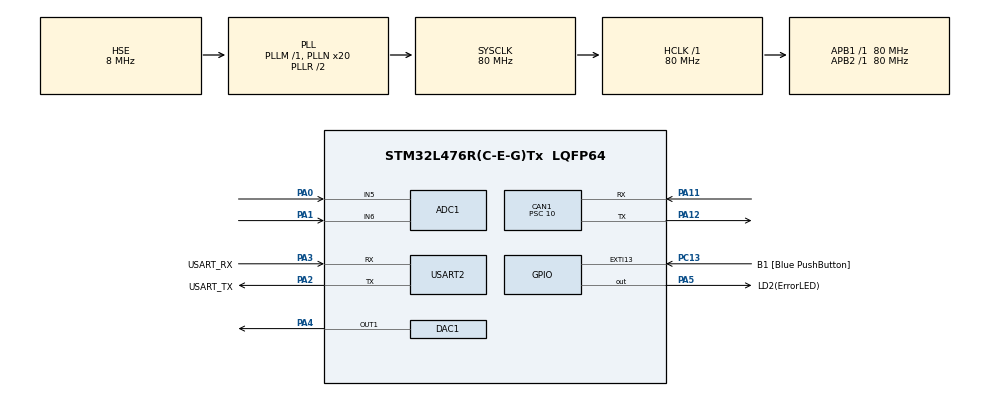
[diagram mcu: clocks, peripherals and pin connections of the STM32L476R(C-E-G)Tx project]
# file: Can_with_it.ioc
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ADC1.Channel-7\#ChannelRegularConversion=ADC_CHANNEL_5
ADC1.Channel-8\#ChannelRegularConversion=ADC_CHANNEL_6
ADC1.ContinuousConvMode=ENABLE
ADC1.DMAContinuousRequests=ENABLE
ADC1.ExternalTrigConv=ADC_EXTERNALTRIG_T6_TRGO
ADC1.ExternalTrigConvEdge=ADC_EXTERNALTRIGCONVEDGE_RISINGFALLING
ADC1.NbrOfConversion=2
ADC1.NbrOfConversionFlag=1
ADC1.OffsetNumber-7\#ChannelRegularConversion=ADC_OFFSET_NONE
ADC1.OffsetNumber-8\#ChannelRegularConversion=ADC_OFFSET_NONE
ADC1.Overrun=ADC_OVR_DATA_PRESERVED
ADC1.Rank-7\#ChannelRegularConversion=1
ADC1.Rank-8\#ChannelRegularConversion=2
ADC1.SamplingTime-7\#ChannelRegularConversion=ADC_SAMPLETIME_247CYCLES_5
ADC1.SamplingTime-8\#ChannelRegularConversion=ADC_SAMPLETIME_247CYCLES_5
ADC1.master=1
CAN1.BS1=CAN_BS1_13TQ
CAN1.BS2=CAN_BS2_2TQ
CAN1.CalculateBaudRate=500000
CAN1.CalculateTimeBit=2000
CAN1.CalculateTimeQuantum=125.0
CAN1.Mode=CAN_MODE_NORMAL
CAN1.Prescaler=10
DAC1.DAC_Trigger-DAC_OUT1=DAC_TRIGGER_T6_TRGO
Dma.ADC1.0.Direction=DMA_PERIPH_TO_MEMORY
Dma.ADC1.0.Instance=DMA1_Channel1
Dma.ADC1.0.MemDataAlignment=DMA_MDATAALIGN_WORD
Dma.ADC1.0.MemInc=DMA_MINC_ENABLE
Dma.ADC1.0.Mode=DMA_CIRCULAR
Dma.ADC1.0.PeriphDataAlignment=DMA_PDATAALIGN_WORD
Dma.ADC1.0.PeriphInc=DMA_PINC_DISABLE
Dma.ADC1.0.Priority=DMA_PRIORITY_VERY_HIGH
Dma.DAC_CH1.1.Direction=DMA_MEMORY_TO_PERIPH
Dma.DAC_CH1.1.Instance=DMA1_Channel3
Dma.DAC_CH1.1.MemDataAlignment=DMA_MDATAALIGN_HALFWORD
Dma.DAC_CH1.1.MemInc=DMA_MINC_ENABLE
Dma.DAC_CH1.1.Mode=DMA_CIRCULAR
Dma.DAC_CH1.1.PeriphDataAlignment=DMA_PDATAALIGN_HALFWORD
Dma.DAC_CH1.1.PeriphInc=DMA_PINC_DISABLE
Dma.DAC_CH1.1.Priority=DMA_PRIORITY_HIGH
Dma.Request0=ADC1
Dma.Request1=DAC_CH1
Mcu.Family=STM32L4
Mcu.Name=STM32L476R(C-E-G)Tx
Mcu.Package=LQFP64
NVIC.CAN1_RX0_IRQn=true\:1\:0\:true\:false\:true\:true\:true\:true
NVIC.CAN1_RX1_IRQn=true\:1\:0\:true\:false\:true\:true\:true\:true
NVIC.CAN1_SCE_IRQn=true\:1\:0\:true\:false\:true\:true\:true\:true
NVIC.CAN1_TX_IRQn=true\:1\:0\:true\:false\:true\:true\:true\:true
NVIC.DMA1_Channel1_IRQn=true\:0\:0\:true\:false\:true\:false\:true\:true
NVIC.DMA1_Channel3_IRQn=true\:0\:0\:true\:false\:true\:false\:true\:true
NVIC.PriorityGroup=NVIC_PRIORITYGROUP_4
NVIC.TIM6_DAC_IRQn=true\:0\:0\:true\:false\:true\:true\:true\:true
NVIC.USART2_IRQn=true\:2\:0\:true\:false\:true\:true\:true\:true
PA0.Signal=ADCx_IN5
PA1.Signal=ADCx_IN6
PA11.Mode=CAN_Activate
PA11.Signal=CAN1_RX
PA12.GPIO_PuPd=GPIO_PULLUP
PA12.Mode=CAN_Activate
PA12.Signal=CAN1_TX
PA13\ (JTMS-SWDIO).GPIO_Label=TMS
PA13\ (JTMS-SWDIO).Mode=Serial_Wire
PA13\ (JTMS-SWDIO).Signal=SYS_JTMS-SWDIO
PA14\ (JTCK-SWCLK).GPIO_Label=TCK
PA14\ (JTCK-SWCLK).Mode=Serial_Wire
PA14\ (JTCK-SWCLK).Signal=SYS_JTCK-SWCLK
PA2.GPIO_Label=USART_TX
PA2.GPIO_Mode=GPIO_MODE_AF_PP
PA2.GPIO_PuPd=GPIO_NOPULL
PA2.GPIO_Speed=GPIO_SPEED_FREQ_VERY_HIGH
PA2.Mode=Asynchronous
PA2.Signal=USART2_TX
PA3.GPIO_Label=USART_RX
PA3.GPIO_Mode=GPIO_MODE_AF_PP
PA3.GPIO_PuPd=GPIO_NOPULL
PA3.GPIO_Speed=GPIO_SPEED_FREQ_VERY_HIGH
PA3.Mode=Asynchronous
PA3.Signal=USART2_RX
PA4.Signal=COMP_DAC11_group
PA5.GPIO_Label=LD2(ErrorLED)
PA5.Signal=GPIO_Output
PB3\ (JTDO-TRACESWO).GPIO_Label=SWO
PB3\ (JTDO-TRACESWO).Signal=SYS_JTDO-SWO
PC13.GPIO_Label=B1 [Blue PushButton]
PC13.GPIO_ModeDefaultEXTI=GPIO_MODE_IT_FALLING
PC13.GPIO_PuPd=GPIO_NOPULL
PC13.Signal=GPXTI13
PC14-OSC32_IN\ (PC14).Signal=RCC_OSC32_IN
PC15-OSC32_OUT\ (PC15).Signal=RCC_OSC32_OUT
PH0-OSC_IN\ (PH0).Mode=HSE-External-Clock-Source
PH0-OSC_IN\ (PH0).Signal=RCC_OSC_IN
PH1-OSC_OUT\ (PH1).Signal=RCC_OSC_OUT
ProjectManager.HeapSize=0x200
ProjectManager.StackSize=0x400
ProjectManager.TargetToolchain=STM32CubeIDE
RCC.ADCFreq_Value=64000000
RCC.AHBFreq_Value=80000000
RCC.APB1Freq_Value=80000000
RCC.APB1TimFreq_Value=80000000
RCC.APB2Freq_Value=80000000
RCC.APB2TimFreq_Value=80000000
RCC.CortexFreq_Value=80000000
RCC.DATA_CACHE_ENABLE=1
RCC.FLatency=FLASH_LATENCY_4
RCC.HCLKFreq_Value=80000000
RCC.HSE_Timout=100
RCC.HSE_VALUE=8000000
RCC.HSICalibrationValue=16
RCC.HSI_VALUE=16000000
RCC.INSTRUCTION_CACHE_ENABLE=1
RCC.LSE_VALUE=32768
RCC.MSICalibrationValue=0
RCC.MSI_VALUE=4000000
RCC.PLLN=20
RCC.PLLSAI1N=16
RCC.PLLSourceVirtual=RCC_PLLSOURCE_HSE
RCC.PREFETCH_ENABLE=1
RCC.PWR_Regulator_Voltage_Scale=PWR_REGULATOR_VOLTAGE_SCALE1
RCC.SYSCLKFreq_VALUE=80000000
RCC.SYSCLKSource=RCC_SYSCLKSOURCE_PLLCLK
RCC.USBFreq_Value=64000000
RCC.VCOOutputFreq_Value=160000000
SH.ADCx_IN5.0=ADC1_IN5,IN5-Single-Ended
SH.ADCx_IN6.0=ADC1_IN6,IN6-Single-Ended
SH.COMP_DAC11_group.0=DAC1_OUT1,DAC_OUT1
TIM6.TIM_MasterOutputTrigger=TIM_TRGO_UPDATE
USART2.VirtualMode-Asynchronous=VM_ASYNC
VP_TIM6_VS_ClockSourceINT.Mode=Enable_Timer
board=NUCLEO-L476RG

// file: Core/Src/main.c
/* USER CODE BEGIN Header */
/**
  ******************************************************************************
  * @file           : main.c
  * @brief          : Main program body
  ******************************************************************************
  * @attention
  *
  * Copyright (c) 2024 STMicroelectronics.
  * All rights reserved.
  *
  * This software is licensed under terms that can be found in the LICENSE file
  * in the root directory of this software component.
  * If no LICENSE file comes with this software, it is provided AS-IS.
  *
  ******************************************************************************
  */
/* USER CODE END Header */
#include "main.h"

/* USER CODE BEGIN PD */
#define ADC1IN5 0
#define ADC1IN6 1
#define BRAKEPRESSURE 2
//#define ADC_VREF 0
/* USER CODE END PD */

ADC_HandleTypeDef hadc1;
DMA_HandleTypeDef hdma_adc1;

CAN_HandleTypeDef hcan1;

DAC_HandleTypeDef hdac1;
DMA_HandleTypeDef hdma_dac_ch1;

TIM_HandleTypeDef htim6;

UART_HandleTypeDef huart2;

/* USER CODE BEGIN PV */
/***************ADC VARIABLES***************/
uint32_t rawValues[2];//array to store values from the adc
uint16_t adcVREF;//variable for vrefint channel
uint32_t adcBuffer[2];//buffer for adcinput
uint16_t brakePressure;

/***************DAC VARIABLES***************/
uint32_t dac_val;//function to write value to the dac
uint32_t getDac;//debugging integer for dac

/***************COMMONDATA VARIABLES***************/
bmsData bmsDataObj = {0};

/***************CAN VARIABLES***************/
uint16_t data[8];

/***************ERROR CODES***************/
char* adcNcalib = "ADC calibration failure!\r\n";
char* potShortPedal = "Potentiometers have shorted!\r\n";
char* deviationCheckFail = "Deviation is above 10%!\r\n";
char* death = "STM die!\r\n";

/***************DATALOGGING***************/
char msg[100];//debugging array for uart

/***************FLAGS***************/
uint8_t runON = 0;

/* USER CODE END PV */

void SystemClock_Config(void);
static void MX_GPIO_Init(void);
static void MX_DMA_Init(void);
static void MX_USART2_UART_Init(void);
static void MX_CAN1_Init(void);
static void MX_TIM6_Init(void);
static void MX_DAC1_Init(void);
static void MX_ADC1_Init(void);
/* USER CODE BEGIN PFP */
uint32_t dacInput(uint16_t adcinput1, uint16_t adcinput2);

void HAL_TIM_PeriodElapsedCallback(TIM_HandleTypeDef *htim){
	dac_val = dacInput(rawValues[0], rawValues[1]);

	if(brakePressure > 600){
		HAL_GPIO_WritePin(BrakeLight_GPIO_Port, BrakeLight_Pin, GPIO_PIN_SET);
	}else{
		HAL_GPIO_WritePin(BrakeLight_GPIO_Port, BrakeLight_Pin, GPIO_PIN_RESET);
	}
}

void HAL_ADC_ConvCpltCallback(ADC_HandleTypeDef *hadc){
	rawValues[0] = adcBuffer[ADC1IN5];
	rawValues[1] = adcBuffer[ADC1IN6];
	brakePressure = adcBuffer[BRAKEPRESSURE];
}

void ErrorLedBlink(){
	HAL_GPIO_WritePin(LD2_GPIO_Port, LD2_Pin, GPIO_PIN_SET);
	HAL_Delay(500);
	HAL_GPIO_WritePin(LD2_GPIO_Port, LD2_Pin, GPIO_PIN_RESET);
	HAL_Delay(500);
}

void HAL_GPIO_EXTI_Callback(uint16_t GPIO_Pin){
	if(RUNON_Pin){
		runON = 1;
	}
//	else if(B1_Pin){
//
//	}

	//for future interrupts
//	else{
//
//	}
}

/* USER CODE END PFP */

int main(void)
{

  /* MCU Configuration--------------------------------------------------------*/

  /* Reset of all peripherals, Initializes the Flash interface and the Systick. */
  HAL_Init();

  /* Configure the system clock */
  SystemClock_Config();

  /* Initialize all configured peripherals */
  MX_GPIO_Init();
  MX_DMA_Init();
  MX_USART2_UART_Init();
  MX_CAN1_Init();
  MX_TIM6_Init();
  MX_DAC1_Init();
  MX_ADC1_Init();
  /* USER CODE BEGIN 2 */
  HAL_ADCEx_Calibration_SetValue(&hadc1, ADC_SINGLE_ENDED, calibrationValue);

  uint32_t calibrationValue = HAL_ADCEx_Calibration_GetValue(&hadc1,ADC_SINGLE_ENDED);
  sprintf(msg, "%lu\r\n", calibrationValue);
  LOGS((uint8_t* )msg, strlen(msg));

  if(HAL_ADCEx_Calibration_Start(&hadc1, ADC_SINGLE_ENDED)!=HAL_OK){
	  LOGS((uint8_t*)adcNcalib,strlen(adcNcalib));
	  ErrorLedBlink();
	  HAL_ADCEx_Calibration_Start(&hadc1, ADC_SINGLE_ENDED);
  }

  HAL_CAN_Start(&hcan1);
  if(canNotification()!=0){
	  Error_Handler();
  }

  HAL_ADC_Start_DMA(&hadc1, adcBuffer, 2);
  HAL_DAC_Start_DMA(&hdac1, DAC_CHANNEL_1, &dac_val, 1, DAC_ALIGN_12B_R);
  HAL_TIM_Base_Start_IT(&htim6);

  /* USER CODE END 2 */

  /* Infinite loop */
  /* USER CODE BEGIN WHILE */
  while (1)
  {
//	  canTransmit(test);
	  sprintf(msg,"adc1 val: %hu\r\nadc2 val: %hu\r\ndac val: %hu\r\n",(uint16_t)rawValues[0],(uint16_t)rawValues[1],(uint16_t)HAL_DAC_GetValue(&hdac1, DAC_CHANNEL_1));
	  LOGS((uint8_t*)msg,strlen(msg));
//
//	  getDac = HAL_DAC_GetValue(&hdac1, DAC_CHANNEL_1);

//	  sprintf(msg,"99 %hu\n",(uint16_t)getDac);

//	  LOGS((uint8_t*)msg,strlen(msg));

	  if(runON==1){
		  HAL_GPIO_WritePin(BUZZER_GPIO_Port, BUZZER_Pin, GPIO_PIN_SET);
		  runON = 0;
	  }else{
		  HAL_GPIO_WritePin(BUZZER_GPIO_Port, BUZZER_Pin, GPIO_PIN_RESET);
	  }

	  HAL_Delay(1000);
    /* USER CODE END WHILE */

  }
}

void SystemClock_Config(void)
{
  RCC_OscInitTypeDef RCC_OscInitStruct = {0};
  RCC_ClkInitTypeDef RCC_ClkInitStruct = {0};

  /** Configure the main internal regulator output voltage
  */
  if (HAL_PWREx_ControlVoltageScaling(PWR_REGULATOR_VOLTAGE_SCALE1) != HAL_OK)
  {
    Error_Handler();
  }

  /** Initializes the RCC Oscillators according to the specified parameters
  * in the RCC_OscInitTypeDef structure.
  */
  RCC_OscInitStruct.OscillatorType = RCC_OSCILLATORTYPE_HSE;
  RCC_OscInitStruct.HSEState = RCC_HSE_BYPASS;
  RCC_OscInitStruct.PLL.PLLState = RCC_PLL_ON;
  RCC_OscInitStruct.PLL.PLLSource = RCC_PLLSOURCE_HSE;
  RCC_OscInitStruct.PLL.PLLM = 1;
  RCC_OscInitStruct.PLL.PLLN = 20;
  RCC_OscInitStruct.PLL.PLLP = RCC_PLLP_DIV7;
  RCC_OscInitStruct.PLL.PLLQ = RCC_PLLQ_DIV2;
  RCC_OscInitStruct.PLL.PLLR = RCC_PLLR_DIV2;
  if (HAL_RCC_OscConfig(&RCC_OscInitStruct) != HAL_OK)
  {
    Error_Handler();
  }

  /** Initializes the CPU, AHB and APB buses clocks
  */
  RCC_ClkInitStruct.ClockType = RCC_CLOCKTYPE_HCLK|RCC_CLOCKTYPE_SYSCLK
                              |RCC_CLOCKTYPE_PCLK1|RCC_CLOCKTYPE_PCLK2;
  RCC_ClkInitStruct.SYSCLKSource = RCC_SYSCLKSOURCE_PLLCLK;
  RCC_ClkInitStruct.AHBCLKDivider = RCC_SYSCLK_DIV1;
  RCC_ClkInitStruct.APB1CLKDivider = RCC_HCLK_DIV1;
  RCC_ClkInitStruct.APB2CLKDivider = RCC_HCLK_DIV1;

  if (HAL_RCC_ClockConfig(&RCC_ClkInitStruct, FLASH_LATENCY_4) != HAL_OK)
  {
    Error_Handler();
  }
}

static void MX_ADC1_Init(void)
{

  ADC_MultiModeTypeDef multimode = {0};
  ADC_ChannelConfTypeDef sConfig = {0};

  /** Common config
  */
  hadc1.Instance = ADC1;
  hadc1.Init.ClockPrescaler = ADC_CLOCK_ASYNC_DIV1;
  hadc1.Init.Resolution = ADC_RESOLUTION_12B;
  hadc1.Init.DataAlign = ADC_DATAALIGN_RIGHT;
  hadc1.Init.ScanConvMode = ADC_SCAN_ENABLE;
  hadc1.Init.EOCSelection = ADC_EOC_SINGLE_CONV;
  hadc1.Init.LowPowerAutoWait = DISABLE;
  hadc1.Init.ContinuousConvMode = ENABLE;
  hadc1.Init.NbrOfConversion = 3;
  hadc1.Init.DiscontinuousConvMode = DISABLE;
  hadc1.Init.ExternalTrigConv = ADC_EXTERNALTRIG_T6_TRGO;
  hadc1.Init.ExternalTrigConvEdge = ADC_EXTERNALTRIGCONVEDGE_RISINGFALLING;
  hadc1.Init.DMAContinuousRequests = ENABLE;
  hadc1.Init.Overrun = ADC_OVR_DATA_PRESERVED;
  hadc1.Init.OversamplingMode = DISABLE;
  if (HAL_ADC_Init(&hadc1) != HAL_OK)
  {
    Error_Handler();
  }

  /** Configure the ADC multi-mode
  */
  multimode.Mode = ADC_MODE_INDEPENDENT;
  if (HAL_ADCEx_MultiModeConfigChannel(&hadc1, &multimode) != HAL_OK)
  {
    Error_Handler();
  }

  /** Configure Regular Channel
  */
  sConfig.Channel = ADC_CHANNEL_5;
  sConfig.Rank = ADC_REGULAR_RANK_1;
  sConfig.SamplingTime = ADC_SAMPLETIME_247CYCLES_5;
  sConfig.SingleDiff = ADC_SINGLE_ENDED;
  sConfig.OffsetNumber = ADC_OFFSET_NONE;
  sConfig.Offset = 0;
  if (HAL_ADC_ConfigChannel(&hadc1, &sConfig) != HAL_OK)
  {
    Error_Handler();
  }

  /** Configure Regular Channel
  */
  sConfig.Channel = ADC_CHANNEL_6;
  sConfig.Rank = ADC_REGULAR_RANK_2;
  if (HAL_ADC_ConfigChannel(&hadc1, &sConfig) != HAL_OK)
  {
    Error_Handler();
  }

  /** Configure Regular Channel
  */
  sConfig.Channel = ADC_CHANNEL_1;
  sConfig.Rank = ADC_REGULAR_RANK_3;
  if (HAL_ADC_ConfigChannel(&hadc1, &sConfig) != HAL_OK)
  {
    Error_Handler();
  }

}

static void MX_CAN1_Init(void)
{

  /* USER CODE BEGIN CAN1_Init 1 */
	CAN_FilterTypeDef sFilterConfig;

  /* USER CODE END CAN1_Init 1 */
  hcan1.Instance = CAN1;
  hcan1.Init.Prescaler = 10;
  hcan1.Init.Mode = CAN_MODE_NORMAL;
  hcan1.Init.SyncJumpWidth = CAN_SJW_1TQ;
  hcan1.Init.TimeSeg1 = CAN_BS1_13TQ;
  hcan1.Init.TimeSeg2 = CAN_BS2_2TQ;
  hcan1.Init.TimeTriggeredMode = DISABLE;
  hcan1.Init.AutoBusOff = DISABLE;
  hcan1.Init.AutoWakeUp = DISABLE;
  hcan1.Init.AutoRetransmission = DISABLE;
  hcan1.Init.ReceiveFifoLocked = DISABLE;
  hcan1.Init.TransmitFifoPriority = DISABLE;
  if (HAL_CAN_Init(&hcan1) != HAL_OK)
  {
    Error_Handler();
  }
  /* USER CODE BEGIN CAN1_Init 2 */
  sFilterConfig.FilterBank = 0;
  sFilterConfig.FilterMode = CAN_FILTERMODE_IDMASK;
  sFilterConfig.FilterScale = CAN_FILTERSCALE_32BIT;
  sFilterConfig.FilterIdHigh = 0x0000;
  sFilterConfig.FilterIdLow = 0x0000;
  sFilterConfig.FilterMaskIdHigh = 0x0000;
  sFilterConfig.FilterMaskIdLow = 0x0000;
  sFilterConfig.FilterFIFOAssignment = CAN_RX_FIFO0;
  sFilterConfig.FilterActivation = ENABLE;
  sFilterConfig.SlaveStartFilterBank = 14;

  if(HAL_CAN_ConfigFilter(&hcan1, &sFilterConfig) != HAL_OK){
      /* Filter configuration Error */
      Error_Handler();
    }

  sFilterConfig.FilterBank = 1;
  sFilterConfig.FilterMode = CAN_FILTERMODE_IDMASK;
  sFilterConfig.FilterScale = CAN_FILTERSCALE_32BIT;
  sFilterConfig.FilterIdHigh = 0x0000;
  sFilterConfig.FilterIdLow = 0x0000;
  sFilterConfig.FilterMaskIdHigh = 0x0000;
  sFilterConfig.FilterMaskIdLow = 0x0000;
  sFilterConfig.FilterFIFOAssignment = CAN_RX_FIFO1;
  sFilterConfig.FilterActivation = ENABLE;
  sFilterConfig.SlaveStartFilterBank = 14;

    if(HAL_CAN_ConfigFilter(&hcan1, &sFilterConfig) != HAL_OK){
        /* Filter configuration Error */
        Error_Handler();
      }
  /* USER CODE END CAN1_Init 2 */

}

static void MX_DAC1_Init(void)
{

  DAC_ChannelConfTypeDef sConfig = {0};

  /** DAC Initialization
  */
  hdac1.Instance = DAC1;
  if (HAL_DAC_Init(&hdac1) != HAL_OK)
  {
    Error_Handler();
  }

  /** DAC channel OUT1 config
  */
  sConfig.DAC_SampleAndHold = DAC_SAMPLEANDHOLD_DISABLE;
  sConfig.DAC_Trigger = DAC_TRIGGER_T6_TRGO;
  sConfig.DAC_OutputBuffer = DAC_OUTPUTBUFFER_ENABLE;
  sConfig.DAC_ConnectOnChipPeripheral = DAC_CHIPCONNECT_DISABLE;
  sConfig.DAC_UserTrimming = DAC_TRIMMING_FACTORY;
  if (HAL_DAC_ConfigChannel(&hdac1, &sConfig, DAC_CHANNEL_1) != HAL_OK)
  {
    Error_Handler();
  }

}

static void MX_TIM6_Init(void)
{

  TIM_MasterConfigTypeDef sMasterConfig = {0};

  htim6.Instance = TIM6;
  htim6.Init.Prescaler = 0;
  htim6.Init.CounterMode = TIM_COUNTERMODE_UP;
  htim6.Init.Period = 65535;
  htim6.Init.AutoReloadPreload = TIM_AUTORELOAD_PRELOAD_DISABLE;
  if (HAL_TIM_Base_Init(&htim6) != HAL_OK)
  {
    Error_Handler();
  }
  sMasterConfig.MasterOutputTrigger = TIM_TRGO_UPDATE;
  sMasterConfig.MasterSlaveMode = TIM_MASTERSLAVEMODE_DISABLE;
  if (HAL_TIMEx_MasterConfigSynchronization(&htim6, &sMasterConfig) != HAL_OK)
  {
    Error_Handler();
  }

}

static void MX_USART2_UART_Init(void)
{

  huart2.Instance = USART2;
  huart2.Init.BaudRate = 115200;
  huart2.Init.WordLength = UART_WORDLENGTH_8B;
  huart2.Init.StopBits = UART_STOPBITS_1;
  huart2.Init.Parity = UART_PARITY_NONE;
  huart2.Init.Mode = UART_MODE_TX_RX;
  huart2.Init.HwFlowCtl = UART_HWCONTROL_NONE;
  huart2.Init.OverSampling = UART_OVERSAMPLING_16;
  huart2.Init.OneBitSampling = UART_ONE_BIT_SAMPLE_DISABLE;
  huart2.AdvancedInit.AdvFeatureInit = UART_ADVFEATURE_NO_INIT;
  if (HAL_UART_Init(&huart2) != HAL_OK)
  {
    Error_Handler();
  }

}

static void MX_DMA_Init(void)
{

  /* DMA controller clock enable */
  __HAL_RCC_DMA1_CLK_ENABLE();

  /* DMA interrupt init */
  /* DMA1_Channel1_IRQn interrupt configuration */
  HAL_NVIC_SetPriority(DMA1_Channel1_IRQn, 0, 0);
  HAL_NVIC_EnableIRQ(DMA1_Channel1_IRQn);
  /* DMA1_Channel3_IRQn interrupt configuration */
  HAL_NVIC_SetPriority(DMA1_Channel3_IRQn, 0, 0);
  HAL_NVIC_EnableIRQ(DMA1_Channel3_IRQn);

}

static void MX_GPIO_Init(void)
{
  GPIO_InitTypeDef GPIO_InitStruct = {0};

  /* GPIO Ports Clock Enable */
  __HAL_RCC_GPIOC_CLK_ENABLE();
  __HAL_RCC_GPIOH_CLK_ENABLE();
  __HAL_RCC_GPIOA_CLK_ENABLE();
  __HAL_RCC_GPIOB_CLK_ENABLE();

  /*Configure GPIO pin Output Level */
  HAL_GPIO_WritePin(LD2_GPIO_Port, LD2_Pin, GPIO_PIN_RESET);

  /*Configure GPIO pin Output Level */
  HAL_GPIO_WritePin(SD_O_GPIO_Port, SD_O_Pin, GPIO_PIN_RESET);

  /*Configure GPIO pin Output Level */
  HAL_GPIO_WritePin(GPIOC, BUZZER_Pin|BrakeLight_Pin, GPIO_PIN_RESET);

  /*Configure GPIO pin : B1_Pin */
  GPIO_InitStruct.Pin = B1_Pin;
  GPIO_InitStruct.Mode = GPIO_MODE_IT_FALLING;
  GPIO_InitStruct.Pull = GPIO_NOPULL;
  HAL_GPIO_Init(B1_GPIO_Port, &GPIO_InitStruct);

  /*Configure GPIO pin : LD2_Pin */
  GPIO_InitStruct.Pin = LD2_Pin;
  GPIO_InitStruct.Mode = GPIO_MODE_OUTPUT_PP;
  GPIO_InitStruct.Pull = GPIO_NOPULL;
  GPIO_InitStruct.Speed = GPIO_SPEED_FREQ_LOW;
  HAL_GPIO_Init(LD2_GPIO_Port, &GPIO_InitStruct);

  /*Configure GPIO pin : SD_O_Pin */
  GPIO_InitStruct.Pin = SD_O_Pin;
  GPIO_InitStruct.Mode = GPIO_MODE_OUTPUT_PP;
  GPIO_InitStruct.Pull = GPIO_NOPULL;
  GPIO_InitStruct.Speed = GPIO_SPEED_FREQ_LOW;
  HAL_GPIO_Init(SD_O_GPIO_Port, &GPIO_InitStruct);

  /*Configure GPIO pin : RUNON_Pin */
  GPIO_InitStruct.Pin = RUNON_Pin;
  GPIO_InitStruct.Mode = GPIO_MODE_IT_RISING;
  GPIO_InitStruct.Pull = GPIO_NOPULL;
  HAL_GPIO_Init(RUNON_GPIO_Port, &GPIO_InitStruct);

  /*Configure GPIO pins : BUZZER_Pin BrakeLight_Pin */
  GPIO_InitStruct.Pin = BUZZER_Pin|BrakeLight_Pin;
  GPIO_InitStruct.Mode = GPIO_MODE_OUTPUT_PP;
  GPIO_InitStruct.Pull = GPIO_NOPULL;
  GPIO_InitStruct.Speed = GPIO_SPEED_FREQ_LOW;
  HAL_GPIO_Init(GPIOC, &GPIO_InitStruct);

  /* EXTI interrupt init*/
  HAL_NVIC_SetPriority(EXTI15_10_IRQn, 0, 0);
  HAL_NVIC_EnableIRQ(EXTI15_10_IRQn);

}

/* USER CODE BEGIN 4 */

//uint32_t dacInput(uint16_t adcinput1, uint16_t adcinput2, uint16_t vref){
//	static uint16_t counter = 0;
//	static uint32_t rawcheck1 = 0;
//	static uint32_t rawcheck2 = 0;
//
//	uint16_t vrefint_cal = *((uint16_t*)VREFINT_CAL_ADDR);
//
//	uint32_t out = 0;
//
//	uint16_t vrefInt;
//	if (vref == 0){
//		vrefInt = 4096;
//	}else{
//		vrefInt = vref;
//	}
//
//	uint32_t raw1 = (3000*(uint32_t)vrefint_cal*adcinput1)/(vrefInt*4096);
//	uint32_t raw2 = (9/8)*(3000*(uint32_t)vrefint_cal*adcinput2)/(vrefInt*4096);
//
//	uint32_t deviationCheck = (abs(raw1-raw2)/4095)*100;
//
//	data[2] = deviationCheck;
//
//	//check if both values are same for 1 second
//	if((raw1!=0) && (raw2!=0) && raw1 == raw2){
//		//check if raw1 is continuously the same
//		if((raw1 != rawcheck1) && (raw2 != rawcheck2)){
//			counter = 0;
//		}
//		//set static value to be compared later
//		rawcheck1 = raw1;
//		rawcheck2 = raw2;
//
//		counter++;
//
//		if(counter > 999){
//			counter = 0;
//			//compare to see if they are still the same
//			if(rawcheck1 == raw1 && rawcheck2 == raw2){
//				out = 0;
//				LOGS(potShortPedal,strlen(potShortPedal));
////				Error_Handler();
//			}
//		}
//	}
//	//check deviation
//	else if(deviationCheck>0.1){
//		out = 0;
////		LOGS(deviationCheckFail,strlen(deviationCheckFail));
////		Error_Handler();
//	}
//	//regular output function(average value)
//	else{
//		raw1 = (raw1)*4096/3300;
//		raw2 = (raw2)*4096/3300;
//		out = ((raw1+raw2)/2);
//	}
//
//	data[0] = raw1;
//	data[1] = raw2;
//
//	return out;
//}

uint32_t dacInput(uint16_t adcinput1, uint16_t adcinput2){
	static uint16_t counter = 0;
	static uint32_t rawcheck1 = 0;
	static uint32_t rawcheck2 = 0;

	uint32_t out = 0;

	uint32_t raw1 = adcinput1;
	uint32_t raw2 = (9/8)*adcinput2;

	uint8_t deviationCheck = ((abs((float)raw1-(float)raw2)/4095.00))*100;

	data[2] = (uint16_t)deviationCheck;

	//check if both values are same for 1 second
	if((raw1!=0) && (raw2!=0) && raw1 == raw2){
		//check if raw1 is continuously the same
		if((raw1 != rawcheck1) && (raw2 != rawcheck2)){
			counter = 0;
		}
		//set static value to be compared later
		rawcheck1 = raw1;
		rawcheck2 = raw2;

		counter++;

		if(counter > 999){
			//compare to see if they are still the same
			if(rawcheck1 == raw1 && rawcheck2 == raw2){
				out = 0;
//				LOGS((uint8_t*)potShortPedal,strlen(potShortPedal));
//				Error_Handler();
			}

			counter = 0;
		}
	}
	//check deviation
	else if(deviationCheck>10){
		HAL_GPIO_WritePin(SD_O_GPIO_Port, SD_O_Pin, GPIO_PIN_SET);
		out = 0;
//		LOGS((uint8_t*)deviationCheckFail,strlen(deviationCheckFail));
//		Error_Handler();
	}
	//regular output function(average value)
	else{
		out = ((raw1+raw2)/2);
	}

	return out;

	data[0] = raw1;
	data[1] = raw2;
}

/* USER CODE END 4 */

void Error_Handler(void)
{
  /* USER CODE BEGIN Error_Handler_Debug */
  /* User can add his own implementation to report the HAL error return state */
  __disable_irq();
  while (1)
  {
	  ErrorLedBlink();
  }
  /* USER CODE END Error_Handler_Debug */
}
